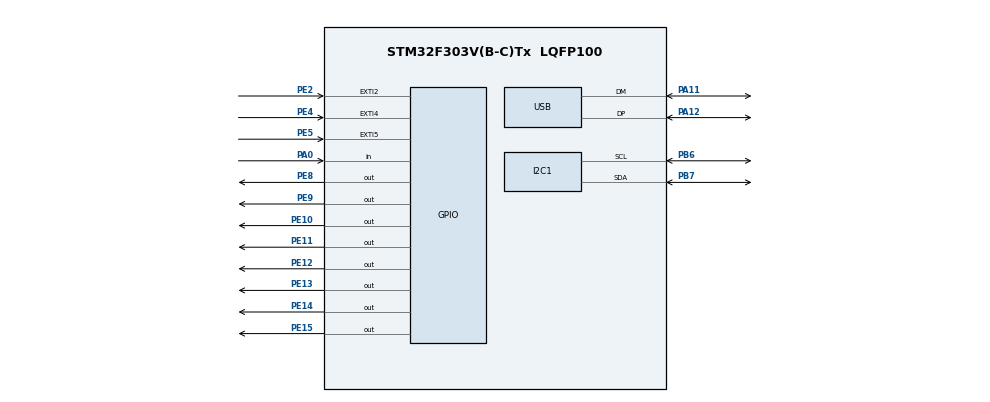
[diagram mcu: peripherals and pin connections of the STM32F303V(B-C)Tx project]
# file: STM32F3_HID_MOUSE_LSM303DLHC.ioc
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Mcu.Family=STM32F3
Mcu.Name=STM32F303V(B-C)Tx
Mcu.Package=LQFP100
NVIC.PriorityGroup=NVIC_PRIORITYGROUP_4
NVIC.TIM3_IRQn=true\:0\:0\:false\:false\:true\:true
NVIC.USB_LP_CAN_RX0_IRQn=true\:0\:0\:false\:false\:true\:true
PA0.Signal=GPIO_Input
PA11.Mode=Device
PA11.Signal=USB_DM
PA12.Mode=Device
PA12.Signal=USB_DP
PB6.Mode=I2C
PB6.Signal=I2C1_SCL
PB7.Mode=I2C
PB7.Signal=I2C1_SDA
PE10.Signal=GPIO_Output
PE11.Signal=GPIO_Output
PE12.Signal=GPIO_Output
PE13.Signal=GPIO_Output
PE14.Signal=GPIO_Output
PE15.Signal=GPIO_Output
PE2.Signal=GPXTI2
PE4.Signal=GPXTI4
PE5.Signal=GPXTI5
PE8.Signal=GPIO_Output
PE9.Signal=GPIO_Output
PF0-OSC_IN.Mode=HSE-External-Oscillator
PF0-OSC_IN.Signal=RCC_OSC_IN
PF1-OSC_OUT.Mode=HSE-External-Oscillator
PF1-OSC_OUT.Signal=RCC_OSC_OUT
ProjectManager.HeapSize=0x200
ProjectManager.StackSize=0x400
ProjectManager.TargetToolchain=EWARM
RCC.AHBFreq_Value=20000000
RCC.APB1CLKDivider=RCC_HCLK_DIV2
RCC.APB1Freq_Value=10000000
RCC.APB1TimFreq_Value=20000000
RCC.APB2Freq_Value=20000000
RCC.APB2TimFreq_Value=20000000
RCC.CortexFreq_Value=20000000
RCC.HCLKFreq_Value=20000000
RCC.HSE_VALUE=20000000
RCC.HSI_VALUE=8000000
RCC.LSE_VALUE=32768
RCC.PLLMUL=RCC_PLL_MUL12
RCC.RCC_PLLsource_Clock_Source_FROM_HSE=RCC_HSE_PREDIV_DIV5
RCC.SYSCLKFreq_VALUE=20000000
RCC.SYSCLKSourceVirtual=RCC_SYSCLKSOURCE_HSE
RCC.USBFreq_Value=48000000
TIM3.Period=19
TIM3.Prescaler=24000
USB_DEVICE.CLASS_NAME_FS=HID
USB_DEVICE.VirtualMode=Hid
USB_DEVICE.VirtualModeFS=Hid_FS
VP_TIM3_VS_ClockSourceINT.Mode=Internal
VP_USB_DEVICE_VS_USB_DEVICE_HID_FS.Mode=HID_FS
board=STM32F3_HID_MOUSE_LSM303DLHC

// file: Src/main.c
/**
  ******************************************************************************
  * File Name          : main.c
  * Description        : Main program body
  ******************************************************************************
  * This notice applies to any and all portions of this file
  * that are not between comment pairs USER CODE BEGIN and
  * USER CODE END. Other portions of this file, whether
  * inserted by the user or by software development tools
  * are owned by their respective copyright owners.
  *
  * Copyright (c) 2017 STMicroelectronics International N.V.
  * All rights reserved.
  *
  * Redistribution and use in source and binary forms, with or without
  * modification, are permitted, provided that the following conditions are met:
  *
  * 1. Redistribution of source code must retain the above copyright notice,
  *    this list of conditions and the following disclaimer.
  * 2. Redistributions in binary form must reproduce the above copyright notice,
  *    this list of conditions and the following disclaimer in the documentation
  *    and/or other materials provided with the distribution.
  * 3. Neither the name of STMicroelectronics nor the names of other
  *    contributors to this software may be used to endorse or promote products
  *    derived from this software without specific written permission.
  * 4. This software, including modifications and/or derivative works of this
  *    software, must execute solely and exclusively on microcontroller or
  *    microprocessor devices manufactured by or for STMicroelectronics.
  * 5. Redistribution and use of this software other than as permitted under
  *    this license is void and will automatically terminate your rights under
  *    this license.
  *
  * THIS SOFTWARE IS PROVIDED BY STMICROELECTRONICS AND CONTRIBUTORS "AS IS"
  * AND ANY EXPRESS, IMPLIED OR STATUTORY WARRANTIES, INCLUDING, BUT NOT
  * LIMITED TO, THE IMPLIED WARRANTIES OF MERCHANTABILITY, FITNESS FOR A
  * PARTICULAR PURPOSE AND NON-INFRINGEMENT OF THIRD PARTY INTELLECTUAL PROPERTY
  * RIGHTS ARE DISCLAIMED TO THE FULLEST EXTENT PERMITTED BY LAW. IN NO EVENT
  * SHALL STMICROELECTRONICS OR CONTRIBUTORS BE LIABLE FOR ANY DIRECT, INDIRECT,
  * INCIDENTAL, SPECIAL, EXEMPLARY, OR CONSEQUENTIAL DAMAGES (INCLUDING, BUT NOT
  * LIMITED TO, PROCUREMENT OF SUBSTITUTE GOODS OR SERVICES; LOSS OF USE, DATA,
  * OR PROFITS; OR BUSINESS INTERRUPTION) HOWEVER CAUSED AND ON ANY THEORY OF
  * LIABILITY, WHETHER IN CONTRACT, STRICT LIABILITY, OR TORT (INCLUDING
  * NEGLIGENCE OR OTHERWISE) ARISING IN ANY WAY OUT OF THE USE OF THIS SOFTWARE,
  * EVEN IF ADVISED OF THE POSSIBILITY OF SUCH DAMAGE.
  *
  ******************************************************************************
  */
#include "main.h"
#include "stm32f3xx_hal.h"
#include "usb_device.h"

/* USER CODE BEGIN Includes */
#include "Accelerometer.h"
#include "LED_Lib.h"
/* USER CODE END Includes */

I2C_HandleTypeDef hi2c1;

TIM_HandleTypeDef htim3;
TIM_HandleTypeDef htim4;

/* USER CODE BEGIN PV */
/* Private variables ---------------------------------------------------------*/
#define LSM_ADDRESS_ACCELEROMETER	0b00110010
int16_t x,y;//,z;// raw accelerometer data
/* USER CODE END PV */

void SystemClock_Config(void);
static void MX_GPIO_Init(void);
static void MX_I2C1_Init(void);
static void MX_TIM3_Init(void);
//static void MX_TIM4_Init(void);

/* USER CODE BEGIN PFP */
/* Private function prototypes -----------------------------------------------*/

/* USER CODE END PFP */

/* USER CODE BEGIN 0 */
void SetLed(uint8_t n, uint8_t state)
{
	uint16_t pin[8] = {GPIO_PIN_9, GPIO_PIN_10, GPIO_PIN_11, GPIO_PIN_12, GPIO_PIN_13, GPIO_PIN_14, GPIO_PIN_15, GPIO_PIN_8};

	HAL_GPIO_WritePin(GPIOE, pin[n], (state) ? GPIO_PIN_SET : GPIO_PIN_RESET);
}

void Write_LSM_Reg(uint8_t device_adr, uint8_t internal_adr, uint8_t data)
{
	uint8_t tx_buff[2];

	tx_buff[0] = internal_adr;
	tx_buff[1] = data;

	HAL_I2C_Master_Transmit(&hi2c1, device_adr, tx_buff, 2, 10000);
};

uint8_t Read_LSM_Reg(uint8_t device_adr, uint8_t internal_adr)
{
	uint8_t tx_buff[1];
	uint8_t rx_buff[1];

	tx_buff[0] = internal_adr;

	HAL_I2C_Master_Transmit(&hi2c1, device_adr, tx_buff, 1, 10000);
	HAL_I2C_Master_Receive(&hi2c1, device_adr + 1, rx_buff, 1, 10000);

	return rx_buff[0];
};

/*void LSM303DLHC_accelerometer_init ()
{
	  Write_LSM_Reg(LSM_ADDRESS_ACCELEROMETER, 0x20, 0b01110111); //CTRL_REG_1_A odr 1600Hz, XEN, YEN, ZEN
	  Write_LSM_Reg(LSM_ADDRESS_ACCELEROMETER, 0x21, 0b00000000); //CTRL_REG_2_A disable filter
	  Write_LSM_Reg(LSM_ADDRESS_ACCELEROMETER, 0x23, 0b10101000); //CTRL_REG_4_A BDU, scale 8g, HI RES
}*/

/*void get_accelerometer_data()
{
	x = (Read_LSM_Reg(LSM_ADDRESS_ACCELEROMETER, 0x29)<<8) +Read_LSM_Reg(LSM_ADDRESS_ACCELEROMETER, 0x28);
	y = (Read_LSM_Reg(LSM_ADDRESS_ACCELEROMETER, 0x2B)<<8) +Read_LSM_Reg(LSM_ADDRESS_ACCELEROMETER, 0x2A);
	//z = (Read_LSM_Reg(LSM_ADDRESS_ACCELEROMETER, 0x2D)<<8) +Read_LSM_Reg(LSM_ADDRESS_ACCELEROMETER, 0x2C);
}*/
/* USER CODE END 0 */

int main(void)
{

  /* MCU Configuration----------------------------------------------------------*/

  /* Reset of all peripherals, Initializes the Flash interface and the Systick. */
  HAL_Init();

  /* Configure the system clock */
  SystemClock_Config();

  /* Initialize all configured peripherals */
  MX_GPIO_Init();
  MX_I2C1_Init();
  MX_USB_DEVICE_Init();
  MX_TIM3_Init();

  /* USER CODE BEGIN 2 */
  Accel_Ini();

  HAL_TIM_Base_Start_IT(&htim3);
  /* USER CODE END 2 */

  /* Infinite loop */
  while (1)
  {

  }

}

/** System Clock Configuration
*/
void SystemClock_Config(void)
{

  RCC_OscInitTypeDef RCC_OscInitStruct;
  RCC_ClkInitTypeDef RCC_ClkInitStruct;
  RCC_PeriphCLKInitTypeDef PeriphClkInit;

    /**Initializes the CPU, AHB and APB busses clocks
    */
  RCC_OscInitStruct.OscillatorType = RCC_OSCILLATORTYPE_HSI|RCC_OSCILLATORTYPE_HSE;
  RCC_OscInitStruct.HSEState = RCC_HSE_ON;
  RCC_OscInitStruct.HSEPredivValue = RCC_HSE_PREDIV_DIV1;
  RCC_OscInitStruct.HSIState = RCC_HSI_ON;
  RCC_OscInitStruct.HSICalibrationValue = 16;
  RCC_OscInitStruct.PLL.PLLState = RCC_PLL_ON;
  RCC_OscInitStruct.PLL.PLLSource = RCC_PLLSOURCE_HSE;
  RCC_OscInitStruct.PLL.PLLMUL = RCC_PLL_MUL6;
  if (HAL_RCC_OscConfig(&RCC_OscInitStruct) != HAL_OK)
  {
    _Error_Handler(__FILE__, __LINE__);
  }

    /**Initializes the CPU, AHB and APB busses clocks
    */
  RCC_ClkInitStruct.ClockType = RCC_CLOCKTYPE_HCLK|RCC_CLOCKTYPE_SYSCLK
                              |RCC_CLOCKTYPE_PCLK1|RCC_CLOCKTYPE_PCLK2;
  RCC_ClkInitStruct.SYSCLKSource = RCC_SYSCLKSOURCE_PLLCLK;
  RCC_ClkInitStruct.AHBCLKDivider = RCC_SYSCLK_DIV2;
  RCC_ClkInitStruct.APB1CLKDivider = RCC_HCLK_DIV1;
  RCC_ClkInitStruct.APB2CLKDivider = RCC_HCLK_DIV1;

  if (HAL_RCC_ClockConfig(&RCC_ClkInitStruct, FLASH_LATENCY_0) != HAL_OK)
  {
    _Error_Handler(__FILE__, __LINE__);
  }

  PeriphClkInit.PeriphClockSelection = RCC_PERIPHCLK_USB|RCC_PERIPHCLK_I2C1;
  PeriphClkInit.I2c1ClockSelection = RCC_I2C1CLKSOURCE_HSI;
  PeriphClkInit.USBClockSelection = RCC_USBCLKSOURCE_PLL;
  if (HAL_RCCEx_PeriphCLKConfig(&PeriphClkInit) != HAL_OK)
  {
    _Error_Handler(__FILE__, __LINE__);
  }

    /**Configure the Systick interrupt time
    */
  HAL_SYSTICK_Config(HAL_RCC_GetHCLKFreq()/1000);

    /**Configure the Systick
    */
  HAL_SYSTICK_CLKSourceConfig(SYSTICK_CLKSOURCE_HCLK);

  /* SysTick_IRQn interrupt configuration */
  HAL_NVIC_SetPriority(SysTick_IRQn, 0, 0);
}

/* I2C1 init function */
static void MX_I2C1_Init(void)
{

  hi2c1.Instance = I2C1;
  hi2c1.Init.Timing = 0x2000090E;
  hi2c1.Init.OwnAddress1 = 0;
  hi2c1.Init.AddressingMode = I2C_ADDRESSINGMODE_7BIT;
  hi2c1.Init.DualAddressMode = I2C_DUALADDRESS_DISABLE;
  hi2c1.Init.OwnAddress2 = 0;
  hi2c1.Init.OwnAddress2Masks = I2C_OA2_NOMASK;
  hi2c1.Init.GeneralCallMode = I2C_GENERALCALL_DISABLE;
  hi2c1.Init.NoStretchMode = I2C_NOSTRETCH_DISABLE;
  if (HAL_I2C_Init(&hi2c1) != HAL_OK)
  {
    _Error_Handler(__FILE__, __LINE__);
  }

    /**Configure Analogue filter
    */
  if (HAL_I2CEx_ConfigAnalogFilter(&hi2c1, I2C_ANALOGFILTER_ENABLE) != HAL_OK)
  {
    _Error_Handler(__FILE__, __LINE__);
  }

    /**Configure Digital filter
    */
  if (HAL_I2CEx_ConfigDigitalFilter(&hi2c1, 0) != HAL_OK)
  {
    _Error_Handler(__FILE__, __LINE__);
  }

}

/* TIM3 init function */
static void MX_TIM3_Init(void)
{

  TIM_ClockConfigTypeDef sClockSourceConfig;
  TIM_MasterConfigTypeDef sMasterConfig;

  htim3.Instance = TIM3;
  htim3.Init.Prescaler = 24000;
  htim3.Init.CounterMode = TIM_COUNTERMODE_UP;
  htim3.Init.Period = 19;
  htim3.Init.ClockDivision = TIM_CLOCKDIVISION_DIV1;
  htim3.Init.AutoReloadPreload = TIM_AUTORELOAD_PRELOAD_DISABLE;
  if (HAL_TIM_Base_Init(&htim3) != HAL_OK)
  {
    _Error_Handler(__FILE__, __LINE__);
  }

  sClockSourceConfig.ClockSource = TIM_CLOCKSOURCE_INTERNAL;
  if (HAL_TIM_ConfigClockSource(&htim3, &sClockSourceConfig) != HAL_OK)
  {
    _Error_Handler(__FILE__, __LINE__);
  }

  sMasterConfig.MasterOutputTrigger = TIM_TRGO_RESET;
  sMasterConfig.MasterSlaveMode = TIM_MASTERSLAVEMODE_DISABLE;
  if (HAL_TIMEx_MasterConfigSynchronization(&htim3, &sMasterConfig) != HAL_OK)
  {
    _Error_Handler(__FILE__, __LINE__);
  }

}

/** Configure pins as
        * Analog
        * Input
        * Output
        * EVENT_OUT
        * EXTI
*/
static void MX_GPIO_Init(void)
{

  GPIO_InitTypeDef GPIO_InitStruct;

  /* GPIO Ports Clock Enable */
  __HAL_RCC_GPIOE_CLK_ENABLE();
  __HAL_RCC_GPIOF_CLK_ENABLE();
  __HAL_RCC_GPIOA_CLK_ENABLE();
  __HAL_RCC_GPIOB_CLK_ENABLE();

  /*Configure GPIO pin Output Level */
  HAL_GPIO_WritePin(GPIOE, GPIO_PIN_8|GPIO_PIN_9|GPIO_PIN_10|GPIO_PIN_11
                          |GPIO_PIN_12|GPIO_PIN_13|GPIO_PIN_14|GPIO_PIN_15, GPIO_PIN_RESET);

  /*Configure GPIO pins : PE2 PE4 PE5 */
  GPIO_InitStruct.Pin = GPIO_PIN_2|GPIO_PIN_4|GPIO_PIN_5;
  GPIO_InitStruct.Mode = GPIO_MODE_IT_RISING;
  GPIO_InitStruct.Pull = GPIO_NOPULL;
  HAL_GPIO_Init(GPIOE, &GPIO_InitStruct);

  /*Configure GPIO pin : PA0 */
  GPIO_InitStruct.Pin = GPIO_PIN_0;
  GPIO_InitStruct.Mode = GPIO_MODE_INPUT;
  GPIO_InitStruct.Pull = GPIO_NOPULL;
  HAL_GPIO_Init(GPIOA, &GPIO_InitStruct);

  /*Configure GPIO pins : PE8 PE9 PE10 PE11
                           PE12 PE13 PE14 PE15 */
  GPIO_InitStruct.Pin = GPIO_PIN_8|GPIO_PIN_9|GPIO_PIN_10|GPIO_PIN_11
                          |GPIO_PIN_12|GPIO_PIN_13|GPIO_PIN_14|GPIO_PIN_15;
  GPIO_InitStruct.Mode = GPIO_MODE_OUTPUT_PP;
  GPIO_InitStruct.Pull = GPIO_NOPULL;
  GPIO_InitStruct.Speed = GPIO_SPEED_FREQ_LOW;
  HAL_GPIO_Init(GPIOE, &GPIO_InitStruct);

}

void _Error_Handler(char * file, int line)
{
  while(1)
  {
  }
}

/************************ (C) COPYRIGHT STMicroelectronics *****END OF FILE****/
